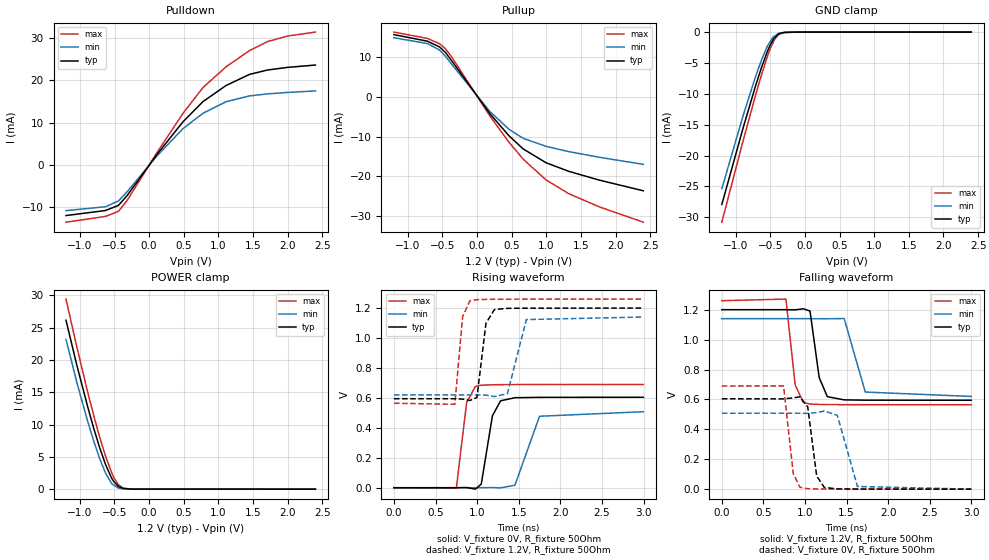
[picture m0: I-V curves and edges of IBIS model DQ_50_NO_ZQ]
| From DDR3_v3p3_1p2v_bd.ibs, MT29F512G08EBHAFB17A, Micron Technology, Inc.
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| MODEL DQ_50_NO_ZQ (50 Ohm Data I/O with no ODT, With No Cal)
[Model]   DQ_50_NO_ZQ
Model_type   I/O
Vinl = 450.000mV
Vinh = 750.000mV
Vmeas = 600.000mV
Vref = 600.000mV
Cref = 0.0pF
Rref = 50.000Ohm
|   typ   min   max
|C_comp   1.240pF   1.143pF   1.340pF
C_comp_pullup   0.6200pF   0.5715pF   0.6700pF
C_comp_pulldown   0.6200pF   0.5715pF   0.6700pF
[Model Spec]
| Input threshold voltage corners
Vinl   0.4500V   0.4200V   0.4800V
Vinh   0.7500V   0.7200V   0.7800V
| Measurement voltage corners
Vmeas   0.6000V   0.5700V   0.6300V
| Timing spec test load voltage corners
Vref   0.6000V   0.5700V   0.6300V
| Dynamic Overshoot Parameters from ONFI4 Specification
D_overshoot_ampl_h   0.80   NA   NA
D_overshoot_ampl_l   0.80   NA   NA
D_overshoot_area_h   0.38n   NA   NA
D_overshoot_area_l   0.38n   NA   NA
[Receiver Thresholds]
Vth   =  0.600V
Vth_min  =  0.5880V
Vth_max  =  0.6120V
Vinh_ac  =  0.150V
Vinh_dc  =  0.100V
Vinl_ac  = -0.150V
Vinl_dc  = -0.100V
Tslew_ac =  5.000ns |Not specified, so set to high value
Threshold_sensitivity = 0.50
Reference_supply Pullup_ref
[Voltage Range]   1.2000V   1.1400V   1.2600V
[Pullup Reference]   1.2000V   1.1400V   1.2600V
| Junction Temperature (Ambient temp is 35C typ, 70C min, 0C max)
[Temperature Range]   50.0   85.0   0.0
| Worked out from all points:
|   slope of the pulldown table from 0 to 0.18 V, typ, clamps not added: 45.8 ohm
|   slope of the pullup table from 0 to 0.18 V, typ, clamps not added: 43.5 ohm
|   GND clamp passes 1 mA (typ) near -0.44 V on its own axis
|   POWER clamp passes 1 mA (typ) near -0.50 V on its own axis
|   falling waveform, V_fixture 1.2V, R_fixture 50Ohm: 20-80 % time 86.1ps typ, 112ps min, 67.3ps max; typ from 1.2 V to 0.594 V
|   rising waveform, V_fixture 0V, R_fixture 50Ohm: 20-80 % time 104ps typ, 150ps min, 72.6ps max; typ from 0 V to 0.604 V
|   rising waveform, V_fixture 1.2V, R_fixture 50Ohm: 20-80 % time 67.9ps typ, 93.3ps min, 50.9ps max; typ from 0.594 V to 1.2 V
|   falling waveform, V_fixture 0V, R_fixture 50Ohm: 20-80 % time 74.8ps typ, 100ps min, 58.5ps max; typ from 0.604 V to 0 V
[Pulldown]
|   Voltage   I(typ)   I(min)   I(max)
-1.2V     -11.9mA    -10.74mA   -13.46mA
-630mV    -10.71mA   -9.821mA   -12.1mA
-442.7mV  -9.496mA   -8.468mA   -10.91mA
-316.7mV  -7.168mA   -6.268mA   -8.307mA
114.4mV   2.519mA    2.175mA    2.96mA
488.3mV   10.18mA    8.565mA    12.17mA
777.9mV   14.95mA    12.2mA     18.26mA
1.11V     18.72mA    14.91mA    23.12mA
1.447V    21.33mA    16.27mA    26.93mA
1.711V    22.38mA    16.75mA    29.08mA
1.997V    22.99mA    17.09mA    30.37mA
2.4V      23.54mA    17.45mA    31.3mA
[GND Clamp]
|   Voltage   I(typ)   I(min)   I(max)
-1.2V     -27.93mA   -25.37mA   -30.8mA
-889.9mV  -15.42mA   -13.44mA   -17.47mA
-716.6mV  -8.847mA   -7.332mA   -10.36mA
-630mV    -5.822mA   -4.6mA     -7.024mA
-542.2mV  -3.131mA   -2.274mA   -3.968mA
-509.5mV  -2.31mA    -1.674mA   -2.913mA
-464.7mV  -1.308mA   -850.6uA   -1.787mA
-442.7mV  -972.8uA   -663uA     -1.241mA
-376mV    -282.1uA   -172.7uA   -322.1uA
-298.8mV  -41.79uA   -56.73uA   -89.82uA
-118.9mV  -137.7nA   -4.668uA   -5.382nA
2.402V    0A         0A         0A
[Pullup]
|   Voltage   I(typ)   I(min)   I(max)
-1.2V     15.67mA    14.89mA    16.31mA
-716.6mV  14.02mA    13.42mA    14.71mA
-542.2mV  12.57mA    11.8mA     13.39mA
-460.4mV  11.25mA    10.3mA     12.17mA
-377.2mV  9.358mA    8.439mA    10.34mA
185.1mV   -4.251mA   -3.681mA   -4.834mA
456.9mV   -9.743mA   -8.135mA   -11.35mA
666.1mV   -13.13mA   -10.46mA   -15.71mA
996.2mV   -16.61mA   -12.48mA   -20.95mA
1.321V    -18.75mA   -13.79mA   -24.37mA
1.759V    -20.96mA   -15.21mA   -27.69mA
2.4V      -23.67mA   -17.01mA   -31.58mA
[POWER Clamp]
|   Voltage   I(typ)   I(min)   I(max)
-1.2V     26.15mA    23.18mA    29.43mA
-1.043V   19.17mA    16.5mA     21.98mA
-889.9mV  12.88mA    10.62mA    15.16mA
-803.3mV  9.553mA    7.573mA    11.54mA
-716.6mV  6.51mA     4.82mA     8.158mA
-628.9mV  3.814mA    2.487mA    5.103mA
-542.2mV  1.733mA    889.2uA    2.608mA
-509.5mV  1.179mA    605.7uA    1.789mA
-442.7mV  400.4uA    165.9uA    681.8uA
-376mV    116.7uA    36.78uA    181.2uA
-257.5mV  4.462uA    7.551uA    6.726uA
2.402V    0A         0A         0A
[Ramp]
R_load = 50
|   typ   min   max
dV/dt_r 3.6255E-01/1.0412E-10   3.0452E-01/1.4883E-10   4.1380E-01/7.2387E-11
dV/dt_f 3.6334E-01/8.5651E-11   3.1198E-01/1.1196E-10   4.1739E-01/6.7087E-11
[Falling Waveform]
V_fixture = 1.2V
V_fixture_min = 1.14V
V_fixture_max = 1.26V
R_fixture = 50Ohm
C_fixture = 0F
|   Time   V(typ)   V(min)   V(max)
0s        1.2V       1.14V      1.26V
770ps     1.2V       1.14V      1.271V
882ps     1.199V     1.14V      696.3mV
980ps     1.206V     1.14V      579.4mV
1.06ns    1.191V     1.14V      569.4mV
1.17ns    746.2mV    1.139V     566.6mV
1.268ns   618.5mV    1.139V     565.6mV
1.47ns    597mV      1.141V     564.9mV
1.724ns   595mV      649.3mV    564.6mV
2.998ns   594.4mV    619.9mV    564.4mV
[Rising Waveform]
V_fixture = 0V
V_fixture_min = 0V
V_fixture_max = 0V
R_fixture = 50Ohm
C_fixture = 0F
|   Time   V(typ)   V(min)   V(max)
0s        102.4uV    210.4uV    27.51uV
750ps     242.3uV    94.29uV    -3.664mV
874ps     1.331mV    57.87uV    569.4mV
980ps     -9.511mV   39.28uV    677mV
1.05ns    24.86mV    332.1uV    684.8mV
1.184ns   480.6mV    1.148mV    687.6mV
1.282ns   580.5mV    -761uV     688.4mV
1.454ns   601.2mV    16.45mV    689mV
1.75ns    603.6mV    477.4mV    689.4mV
2.998ns   604.4mV    507.7mV    689.7mV
[Rising Waveform]
V_fixture = 1.2V
V_fixture_min = 1.14V
V_fixture_max = 1.26V
R_fixture = 50Ohm
C_fixture = 0F
|   Time   V(typ)   V(min)   V(max)
0s        594.4mV    620mV      564.4mV
732ps     594.5mV    619.8mV    557.4mV
826ps     591.9mV    619.7mV    1.143V
914ps     582.7mV    619.7mV    1.249V
998ps     603mV      620mV      1.256V
1.106ns   1.098V     618.2mV    1.258V
1.208ns   1.19V      608.9mV    1.259V
1.364ns   1.198V     628.1mV    1.259V
1.592ns   1.199V     1.123V     1.26V
2.998ns   1.2V       1.14V      1.26V
[Falling Waveform]
|Gnd
V_fixture = 0V
V_fixture_min = 0V
V_fixture_max = 0V
R_fixture = 50Ohm
C_fixture = 0F
|   Time   V(typ)   V(min)   V(max)
0s        604.3mV    507.7mV    689.7mV
742ps     603.8mV    507.9mV    690.2mV
858ps     610.4mV    508mV      105.6mV
938ps     617.4mV    507.6mV    12.87mV
1.032ns   550.4mV    507mV      3.344mV
1.14ns    88.04mV    511.8mV    1.701mV
1.232ns   11.33mV    522.8mV    1.159mV
1.388ns   1.824mV    493.8mV    694.5uV
1.63ns    742.9uV    17.86mV    385uV
2.998ns   86.27uV    166.3uV    20.42uV
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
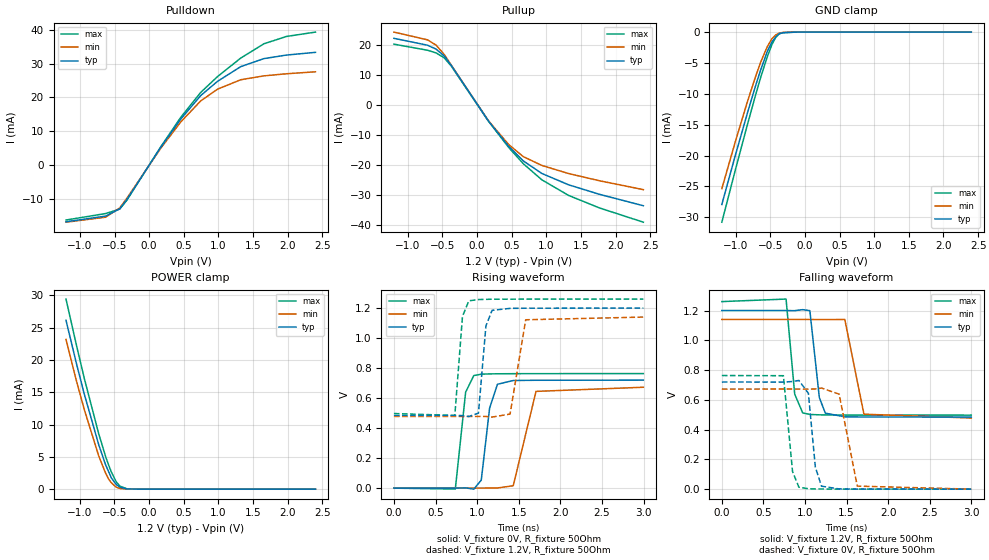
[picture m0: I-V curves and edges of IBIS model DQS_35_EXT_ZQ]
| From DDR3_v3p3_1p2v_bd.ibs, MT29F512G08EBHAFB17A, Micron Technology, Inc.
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| MODEL DQS_35_EXT_ZQ (35 Ohm Data Strobe I/O with no ODT, With ZQ Cal)
[Model]   DQS_35_EXT_ZQ
Model_type   I/O
Vinl = 450.000mV
Vinh = 750.000mV
Vmeas = 600.000mV
Vref = 600.000mV
Cref = 0.0pF
Rref = 50.000Ohm
|   typ   min   max
|C_comp   1.240pF   1.143pF   1.340pF
C_comp_pullup   0.6200pF   0.5715pF   0.6700pF
C_comp_pulldown   0.6200pF   0.5715pF   0.6700pF
[Model Spec]
| Input threshold voltage corners
Vinl   0.4500V   0.4200V   0.4800V
Vinh   0.7500V   0.7200V   0.7800V
| Measurement voltage corners
Vmeas   0.6000V   0.5700V   0.6300V
| Timing spec test load voltage corners
Vref   0.6000V   0.5700V   0.6300V
| Dynamic Overshoot Parameters from ONFI4 Specification
D_overshoot_ampl_h   0.80   NA   NA
D_overshoot_ampl_l   0.80   NA   NA
D_overshoot_area_h   0.38n   NA   NA
D_overshoot_area_l   0.38n   NA   NA
[Receiver Thresholds]
|Vth   =  0.600V
|Vth_min  =  0.5880V
|Vth_max  =  0.6120V
|Vinh_ac  =  0.150V
|Vinh_dc  =  0.100V
|Vinl_ac  = -0.150V
|Vinl_dc  = -0.100V
|Tslew_ac =  5.000ns |Not specified, so set to high value
|Threshold_sensitivity = 0.50
|Reference_supply Pullup_ref
Vcross_low   = 0.480V
Vcross_high  = 0.720V
Vdiff_ac   = 300mV
Vdiff_dc   = 200mV
Tdiffslew_ac = 10.000ns |Not specified, so set to high value
[Voltage Range]   1.2000V   1.1400V   1.2600V
[Pullup Reference]   1.2000V   1.1400V   1.2600V
| Junction Temperature (Ambient temp is 35C typ, 70C min, 0C max)
[Temperature Range]   50.0   85.0   0.0
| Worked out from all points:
|   slope of the pulldown table from 0 to 0.18 V, typ, clamps not added: 32.3 ohm
|   slope of the pullup table from 0 to 0.18 V, typ, clamps not added: 30.7 ohm
|   GND clamp passes 1 mA (typ) near -0.44 V on its own axis
|   POWER clamp passes 1 mA (typ) near -0.49 V on its own axis
|   falling waveform, V_fixture 1.2V, R_fixture 50Ohm: 20-80 % time 73.8ps typ, 92ps min, 62.6ps max; typ from 1.2 V to 0.484 V
|   rising waveform, V_fixture 0V, R_fixture 50Ohm: 20-80 % time 90.4ps typ, 122ps min, 66.9ps max; typ from 0 V to 0.72 V
|   rising waveform, V_fixture 1.2V, R_fixture 50Ohm: 20-80 % time 56.5ps typ, 73.7ps min, 44.8ps max; typ from 0.484 V to 1.2 V
|   falling waveform, V_fixture 0V, R_fixture 50Ohm: 20-80 % time 68.4ps typ, 92.3ps min, 56ps max; typ from 0.72 V to 0 V
[Pulldown]
|   Voltage   I(typ)   I(min)   I(max)
-1.2V     -16.86mA   -16.98mA   -16.34mA
-629.2mV  -15.18mA   -15.51mA   -14.42mA
-423.8mV  -12.99mA   -12.74mA   -13.09mA
-320.5mV  -10.25mA   -9.863mA   -10.44mA
163.4mV   5.072mA    4.806mA    5.216mA
456.9mV   13.59mA    12.73mA    14.1mA
744.8mV   20.54mA    18.95mA    21.47mA
986.5mV   24.74mA    22.42mA    26.14mA
1.322V    29.1mA     25.21mA    31.63mA
1.656V    31.47mA    26.36mA    35.86mA
1.98V     32.52mA    26.98mA    38.03mA
2.4V      33.33mA    27.57mA    39.33mA
[GND Clamp]
|   Voltage   I(typ)   I(min)   I(max)
-1.2V     -27.93mA   -25.37mA   -30.8mA
-1.001V   -19.8mA    -17.6mA    -22.17mA
-831.8mV  -13.17mA   -11.32mA   -15.04mA
-715.2mV  -8.785mA   -7.288mA   -10.3mA
-639.3mV  -6.135mA   -4.883mA   -7.353mA
-544.8mV  -3.169mA   -2.381mA   -4.033mA
-475.5mV  -1.572mA   -1.055mA   -1.987mA
-423.8mV  -806.4uA   -480uA     -904.5uA
-372.2mV  -243.3uA   -177uA     -295.9uA
-320.5mV  -109.7uA   -55.24uA   -92.33uA
-118.9mV  0A         0A         -721.1nA
2.402V    0A         0A         0A
[Pullup]
|   Voltage   I(typ)   I(min)   I(max)
-1.2V     22.12mA    24.19mA    20.18mA
-715.2mV  19.83mA    21.61mA    18.16mA
-591.2mV  18.53mA    19.86mA    17.27mA
-474.2mV  16.25mA    16.76mA    15.63mA
-372.2mV  13.1mA     13.2mA     12.89mA
163.4mV   -5.339mA   -5.249mA   -5.385mA
456.9mV   -13.8mA    -13.21mA   -14.18mA
669.6mV   -18.66mA   -17.24mA   -19.61mA
936mV     -22.81mA   -20.14mA   -24.92mA
1.321V    -26.56mA   -22.82mA   -30.09mA
1.765V    -29.72mA   -25.21mA   -34.24mA
2.4V      -33.52mA   -28.17mA   -38.99mA
[POWER Clamp]
|   Voltage   I(typ)   I(min)   I(max)
-1.2V     26.15mA    23.18mA    29.43mA
-1.045V   19.27mA    16.59mA    22.09mA
-934.4mV  14.65mA    12.27mA    17.09mA
-728mV    6.895mA    5.162mA    8.593mA
-631.2mV  3.86mA     2.547mA    5.163mA
-590.1mV  2.845mA    1.66mA     3.888mA
-544.8mV  1.74mA     985.1uA    2.649mA
-475.5mV  736.6uA    310.2uA    1.155mA
-422.6mV  325.1uA    108.6uA    475.8uA
-320.5mV  34.77uA    7.16uA     55.39uA
-118.9mV  345.5nA    0A         220.3nA
2.402V    0A         0A         0A
[Ramp]
R_load = 50
|   typ   min   max
dV/dt_r 4.3179E-01/8.9457E-11   4.0333E-01/1.2160E-10   4.5802E-01/6.6614E-11
dV/dt_f 4.2953E-01/7.3359E-11   3.9722E-01/9.1640E-11   4.5760E-01/6.2165E-11
[Falling Waveform]
V_fixture = 1.2V
V_fixture_min = 1.14V
V_fixture_max = 1.26V
R_fixture = 50Ohm
C_fixture = 0F
|   Time   V(typ)   V(min)   V(max)
0s        1.2V       1.14V      1.26V
772ps     1.2V       1.14V      1.277V
876ps     1.199V     1.14V      638.1mV
972ps     1.206V     1.14V      512.2mV
1.058ns   1.199V     1.14V      502mV
1.172ns   615mV      1.139V     499.3mV
1.244ns   510.5mV    1.139V     498.6mV
1.478ns   485.9mV    1.14V      497.8mV
1.708ns   484.8mV    503.6mV    497.6mV
2.998ns   484.1mV    477.9mV    497.3mV
[Rising Waveform]
V_fixture = 0V
V_fixture_min = 0V
V_fixture_max = 0V
R_fixture = 50Ohm
C_fixture = 0F
|   Time   V(typ)   V(min)   V(max)
0s        95.85uV    205.5uV    27.18uV
738ps     103.3uV    97.07uV    -5.894mV
862ps     1.65mV     58.53uV    639.6mV
960ps     -6.741mV   37.64uV    750.4mV
1.05ns    53.79mV    271.6uV    759.5mV
1.15ns    533.3mV    1.274mV    761.3mV
1.244ns   692.2mV    1.268mV    762.1mV
1.434ns   717.3mV    15.89mV    762.7mV
1.708ns   718.9mV    644.8mV    763.1mV
2.998ns   719.7mV    672.4mV    763.4mV
[Rising Waveform]
V_fixture = 1.2V
V_fixture_min = 1.14V
V_fixture_max = 1.26V
R_fixture = 50Ohm
C_fixture = 0F
|   Time   V(typ)   V(min)   V(max)
0s        484.1mV    477.9mV    497.3mV
732ps     484.2mV    477.7mV    484.4mV
824ps     483.5mV    477.7mV    1.144V
900ps     477.3mV    477.7mV    1.248V
1.016ns   499.9mV    477.9mV    1.257V
1.106ns   1.082V     477.7mV    1.258V
1.18ns    1.185V     473.7mV    1.259V
1.396ns   1.198V     493.5mV    1.259V
1.584ns   1.199V     1.122V     1.26V
2.998ns   1.2V       1.14V      1.26V
[Falling Waveform]
|Gnd
V_fixture = 0V
V_fixture_min = 0V
V_fixture_max = 0V
R_fixture = 50Ohm
C_fixture = 0F
|   Time   V(typ)   V(min)   V(max)
0s        719.7mV    672.4mV    763.4mV
740ps     719.3mV    672.6mV    762.1mV
850ps     723.2mV    672.6mV    118.6mV
926ps     730.2mV    672.4mV    13.34mV
1.04ns    644.6mV    671.9mV    2.74mV
1.124ns   147.5mV    673.3mV    1.709mV
1.198ns   20.13mV    679.2mV    1.197mV
1.41ns    1.478mV    638.3mV    612.1uV
1.628ns   722.1uV    20.47mV    366.7uV
2.998ns   81.7uV     169.4uV    16.57uV
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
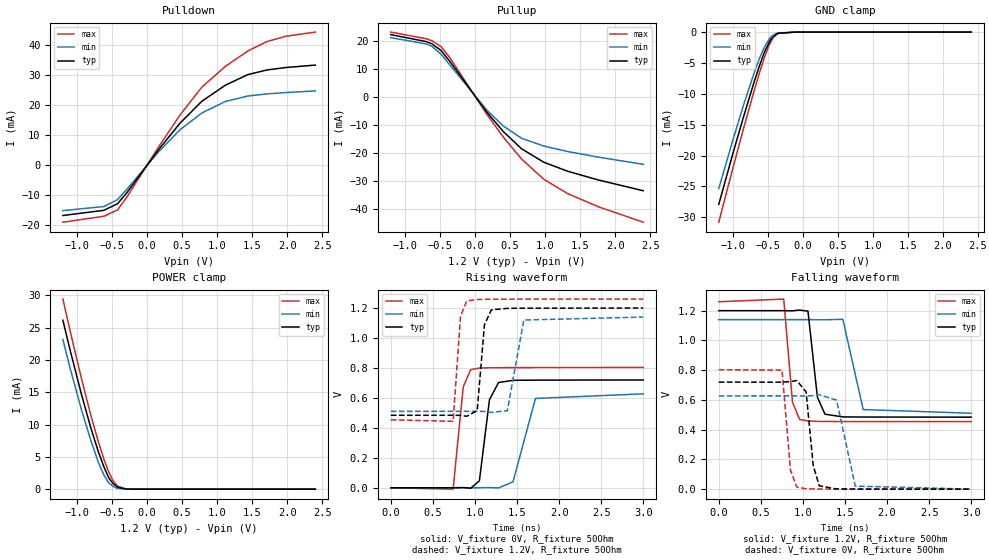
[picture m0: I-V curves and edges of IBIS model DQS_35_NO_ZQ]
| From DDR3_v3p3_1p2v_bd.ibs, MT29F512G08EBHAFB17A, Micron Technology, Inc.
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| MODEL DQS_35_NO_ZQ (35 Ohm Data Strobe I/O with no ODT, With No Cal)
[Model]   DQS_35_NO_ZQ
Model_type   I/O
Vinl = 450.000mV
Vinh = 750.000mV
Vmeas = 600.000mV
Vref = 600.000mV
Cref = 0.0pF
Rref = 50.000Ohm
|   typ   min   max
|C_comp   1.240pF   1.143pF   1.340pF
C_comp_pullup   0.6200pF   0.5715pF   0.6700pF
C_comp_pulldown   0.6200pF   0.5715pF   0.6700pF
[Model Spec]
| Input threshold voltage corners
Vinl   0.4500V   0.4200V   0.4800V
Vinh   0.7500V   0.7200V   0.7800V
| Measurement voltage corners
Vmeas   0.6000V   0.5700V   0.6300V
| Timing spec test load voltage corners
Vref   0.6000V   0.5700V   0.6300V
| Dynamic Overshoot Parameters from ONFI4 Specification
D_overshoot_ampl_h   0.80   NA   NA
D_overshoot_ampl_l   0.80   NA   NA
D_overshoot_area_h   0.38n   NA   NA
D_overshoot_area_l   0.38n   NA   NA
[Receiver Thresholds]
|Vth   =  0.600V
|Vth_min  =  0.5880V
|Vth_max  =  0.6120V
|Vinh_ac  =  0.150V
|Vinh_dc  =  0.100V
|Vinl_ac  = -0.150V
|Vinl_dc  = -0.100V
|Tslew_ac =  5.000ns |Not specified, so set to high value
|Threshold_sensitivity = 0.50
|Reference_supply Pullup_ref
Vcross_low   = 0.480V
Vcross_high  = 0.720V
Vdiff_ac   = 300mV
Vdiff_dc   = 200mV
Tdiffslew_ac = 10.000ns |Not specified, so set to high value
[Voltage Range]   1.2000V   1.1400V   1.2600V
[Pullup Reference]   1.2000V   1.1400V   1.2600V
| Junction Temperature (Ambient temp is 35C typ, 70C min, 0C max)
[Temperature Range]   50.0   85.0   0.0
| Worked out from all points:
|   slope of the pulldown table from 0 to 0.18 V, typ, clamps not added: 32.3 ohm
|   slope of the pullup table from 0 to 0.18 V, typ, clamps not added: 30.7 ohm
|   GND clamp passes 1 mA (typ) near -0.44 V on its own axis
|   POWER clamp passes 1 mA (typ) near -0.49 V on its own axis
|   falling waveform, V_fixture 1.2V, R_fixture 50Ohm: 20-80 % time 73.9ps typ, 97.1ps min, 57.8ps max; typ from 1.2 V to 0.484 V
|   rising waveform, V_fixture 0V, R_fixture 50Ohm: 20-80 % time 90.1ps typ, 133ps min, 62.2ps max; typ from 0 V to 0.72 V
|   rising waveform, V_fixture 1.2V, R_fixture 50Ohm: 20-80 % time 56.3ps typ, 76ps min, 42.8ps max; typ from 0.484 V to 1.2 V
|   falling waveform, V_fixture 0V, R_fixture 50Ohm: 20-80 % time 68.9ps typ, 96.1ps min, 53.2ps max; typ from 0.72 V to 0 V
[Pulldown]
|   Voltage   I(typ)   I(min)   I(max)
-1.2V     -16.86mA   -15.23mA   -19.09mA
-615.2mV  -15.12mA   -13.87mA   -17.11mA
-421.3mV  -12.94mA   -11.55mA   -15.02mA
-290.4mV  -9.333mA   -8.176mA   -10.81mA
161.2mV   5.001mA    4.302mA    5.889mA
470.4mV   13.95mA    11.75mA    16.66mA
782mV     21.27mA    17.35mA    25.98mA
1.12V     26.66mA    21.21mA    32.95mA
1.438V    30.15mA    23.01mA    38.04mA
1.708V    31.69mA    23.71mA    41.17mA
1.98V     32.52mA    24.17mA    42.95mA
2.4V      33.33mA    24.71mA    44.34mA
[GND Clamp]
|   Voltage   I(typ)   I(min)   I(max)
-1.2V     -27.93mA   -25.37mA   -30.8mA
-1.001V   -19.8mA    -17.6mA    -22.17mA
-852.3mV  -13.96mA   -12.06mA   -15.89mA
-693.8mV  -8.039mA   -6.581mA   -9.464mA
-614mV    -5.316mA   -4.134mA   -6.424mA
-544.8mV  -3.169mA   -2.365mA   -4.015mA
-483.6mV  -1.759mA   -1.213mA   -2.185mA
-460.8mV  -1.234mA   -813.7uA   -1.698mA
-421.3mV  -777.3uA   -482.6uA   -857uA
-358.3mV  -207.5uA   -134.2uA   -221.1uA
-107.6mV  0A         0A         -190.2nA
2.402V    0A         0A         0A
[Pullup]
|   Voltage   I(typ)   I(min)   I(max)
-1.2V     22.12mA    21.04mA    23.03mA
-693.8mV  19.64mA    18.82mA    20.65mA
-614mV    18.85mA    17.96mA    19.95mA
-484.3mV  16.48mA    15.19mA    17.87mA
-357.1mV  12.56mA    11.3mA     13.89mA
169.6mV   -5.536mA   -4.8mA     -6.293mA
405.2mV   -12.44mA   -10.47mA   -14.41mA
664.8mV   -18.56mA   -14.81mA   -22.21mA
982.3mV   -23.36mA   -17.59mA   -29.43mA
1.321V    -26.56mA   -19.53mA   -34.52mA
1.761V    -29.69mA   -21.55mA   -39.24mA
2.4V      -33.52mA   -24.09mA   -44.73mA
[POWER Clamp]
|   Voltage   I(typ)   I(min)   I(max)
-1.2V     26.15mA    23.18mA    29.43mA
-1.097V   21.52mA    18.73mA    24.5mA
-931mV    14.51mA    12.14mA    16.94mA
-800.4mV  9.443mA    7.504mA    11.41mA
-693.8mV  5.787mA    4.158mA    7.333mA
-614mV    3.434mA    2.151mA    4.606mA
-546mV    1.761mA    987.4uA    2.65mA
-484.3mV  864.2uA    416.9uA    1.298mA
-420.1mV  312uA      120.1uA    451.4uA
-295.3mV  12.82uA    8.023uA    30.55uA
-118.9mV  345.5nA    0A         0A
2.402V    0A         0A         0A
[Ramp]
R_load = 50
|   typ   min   max
dV/dt_r 4.3179E-01/8.9376E-11   3.7625E-01/1.3207E-10   4.8191E-01/6.1711E-11
dV/dt_f 4.2953E-01/7.3479E-11   3.7776E-01/9.6593E-11   4.8349E-01/5.7519E-11
[Falling Waveform]
V_fixture = 1.2V
V_fixture_min = 1.14V
V_fixture_max = 1.26V
R_fixture = 50Ohm
C_fixture = 0F
|   Time   V(typ)   V(min)   V(max)
0s        1.2V       1.14V      1.26V
772ps     1.2V       1.14V      1.278V
876ps     1.199V     1.14V      584.5mV
960ps     1.204V     1.14V      469.5mV
1.06ns    1.197V     1.14V      458.2mV
1.172ns   618mV      1.139V     455.9mV
1.262ns   503.9mV    1.139V     455.2mV
1.474ns   485.9mV    1.142V     454.7mV
1.716ns   484.8mV    535.2mV    454.4mV
2.998ns   484.1mV    510.3mV    454.2mV
[Rising Waveform]
V_fixture = 0V
V_fixture_min = 0V
V_fixture_max = 0V
R_fixture = 50Ohm
C_fixture = 0F
|   Time   V(typ)   V(min)   V(max)
0s        96.6uV     205.2uV    25.34uV
740ps     81.11uV    95.8uV     -9.124mV
860ps     1.619mV    58.54uV    673.2mV
948ps     -3.318mV   39.55uV    788.7mV
1.052ns   46.42mV    318.3uV    799.6mV
1.172ns   588.5mV    1.345mV    801.5mV
1.28ns    703mV      -577.8uV   802.1mV
1.452ns   717.6mV    40.3mV     802.6mV
1.718ns   718.9mV    596.6mV    802.9mV
2.998ns   719.7mV    627.3mV    803.2mV
[Rising Waveform]
V_fixture = 1.2V
V_fixture_min = 1.14V
V_fixture_max = 1.26V
R_fixture = 50Ohm
C_fixture = 0F
|   Time   V(typ)   V(min)   V(max)
0s        484.1mV    510.3mV    454.2mV
740ps     484.2mV    510.1mV    443.6mV
828ps     483.5mV    510.1mV    1.144V
902ps     477.6mV    510.1mV    1.248V
1.026ns   514.9mV    510.4mV    1.257V
1.112ns   1.088V     509.7mV    1.258V
1.194ns   1.188V     503.9mV    1.259V
1.384ns   1.198V     514.5mV    1.259V
1.58ns    1.199V     1.12V      1.26V
2.998ns   1.2V       1.14V      1.26V
[Falling Waveform]
|Gnd
V_fixture = 0V
V_fixture_min = 0V
V_fixture_max = 0V
R_fixture = 50Ohm
C_fixture = 0F
|   Time   V(typ)   V(min)   V(max)
0s        719.7mV    627.2mV    803.2mV
752ps     719.2mV    627.5mV    800.2mV
852ps     723.3mV    627.5mV    128.7mV
928ps     730.2mV    627.2mV    13.09mV
1.038ns   653.2mV    626.7mV    2.731mV
1.122ns   160.4mV    628.4mV    1.663mV
1.194ns   22.53mV    635.2mV    1.172mV
1.4ns     1.564mV    598.2mV    607.2uV
1.622ns   727.4uV    20.51mV    357.3uV
2.998ns   77.61uV    167.7uV    15.93uV
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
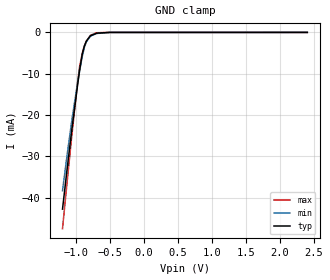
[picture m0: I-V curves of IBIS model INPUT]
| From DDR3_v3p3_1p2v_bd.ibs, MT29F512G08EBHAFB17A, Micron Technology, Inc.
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| MODEL INPUT (Input Input Model)
[Model]   INPUT
Model_type   Input
Vinl = 450.000mV
Vinh = 750.000mV
|   typ   min   max
|C_comp   1.984pF   1.826pF   2.126pF
C_comp_power_clamp   0.9920pF   0.9130pF   1.0630pF
C_comp_gnd_clamp   0.9920pF   0.9130pF   1.0630pF
[Model Spec]
| Input threshold voltage corners
Vinl   0.4500V   0.4200V   0.4800V
Vinh   0.7500V   0.7200V   0.7800V
| Dynamic Overshoot Parameters from ONFI4 Specification
D_overshoot_ampl_h   0.80   NA   NA
D_overshoot_ampl_l   0.80   NA   NA
D_overshoot_area_h   0.38n   NA   NA
D_overshoot_area_l   0.38n   NA   NA
[Receiver Thresholds]
Vth   =  0.600V
Vth_min  =  0.5880V
Vth_max  =  0.6120V
Vinh_ac  =  0.150V
Vinh_dc  =  0.100V
Vinl_ac  = -0.150V
Vinl_dc  = -0.100V
Tslew_ac =  5.000ns |Not specified, so set to high value
Threshold_sensitivity = 0.50
Reference_supply Power_clamp_ref
[Voltage Range]   1.2000V   1.1400V   1.2600V
[POWER Clamp Reference]   1.2000V   1.1400V   1.2600V
| Junction Temperature (Ambient temp is 35C typ, 70C min, 0C max)
[Temperature Range]   50.0   85.0   0.0
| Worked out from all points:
|   GND clamp passes 1 mA (typ) near -0.80 V on its own axis
[GND Clamp]
|   Voltage   I(typ)   I(min)   I(max)
-1.2V     -42.73mA   -38.29mA   -47.46mA
-1.13V    -32.69mA   -29.34mA   -35.77mA
-1.06V    -23.12mA   -20.92mA   -24.48mA
-980mV    -12.91mA   -12.36mA   -12.23mA
-950mV    -9.296mA   -9.444mA   -8.433mA
-910mV    -5.286mA   -5.843mA   -5.055mA
-880mV    -3.352mA   -3.711mA   -3.357mA
-850mV    -2.123mA   -2.283mA   -2.152mA
-790mV    -839.4uA   -917.2uA   -718.8uA
-700mV    -194.7uA   -270.1uA   -91.56uA
-510mV    -4.206uA   -9.012uA   -706.7nA
2.4V      0A         0A         0A
[POWER Clamp]
|   Voltage   I(typ)   I(min)   I(max)
-1.2V     0A         0A         0A
0V        0A         0A         0A
2.4V      0A         0A         0A
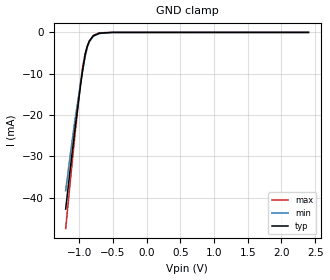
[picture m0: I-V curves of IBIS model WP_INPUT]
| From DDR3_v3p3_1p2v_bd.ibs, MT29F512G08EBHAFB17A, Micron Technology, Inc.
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| MODEL WP_INPUT (WP Input Model)
[Model]   WP_INPUT
Model_type   Input
Vinl = 240.000mV
Vinh = 960.000mV
|   typ   min   max
|C_comp   2.193pF   2.000pF   2.296pF
C_comp_power_clamp   1.0965pF   1.0000pF   1.1480pF
C_comp_gnd_clamp   1.0965pF   1.0000pF   1.1480pF
[Model Spec]
| Input threshold voltage corners
Vinl   0.2400V   0.2280V   0.2520V
Vinh   0.9600V   0.9120V   1.0080V
| Dynamic Overshoot Parameters from ONFI4 Specification
D_overshoot_ampl_h   0.80   NA   NA
D_overshoot_ampl_l   0.80   NA   NA
D_overshoot_area_h   0.38n   NA   NA
D_overshoot_area_l   0.38n   NA   NA
[Voltage Range]   1.2000V   1.1400V   1.2600V
| Junction Temperature (Ambient temp is 35C typ, 70C min, 0C max)
[Temperature Range]   50.0   85.0   0.0
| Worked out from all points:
|   GND clamp passes 1 mA (typ) near -0.80 V on its own axis
[GND Clamp]
|   Voltage   I(typ)   I(min)   I(max)
-1.2V     -42.73mA   -38.29mA   -47.46mA
-1.13V    -32.69mA   -29.34mA   -35.77mA
-1.06V    -23.12mA   -20.92mA   -24.48mA
-980mV    -12.91mA   -12.36mA   -12.23mA
-950mV    -9.296mA   -9.444mA   -8.433mA
-910mV    -5.286mA   -5.843mA   -5.055mA
-880mV    -3.352mA   -3.711mA   -3.357mA
-850mV    -2.123mA   -2.283mA   -2.152mA
-790mV    -839.4uA   -917.2uA   -718.8uA
-700mV    -194.7uA   -270.1uA   -91.56uA
-510mV    -4.206uA   -9.012uA   -706.7nA
2.4V      0A         0A         0A
[POWER Clamp]
|   Voltage   I(typ)   I(min)   I(max)
-1.2V     0A         0A         0A
0V        0A         0A         0A
2.4V      0A         0A         0A
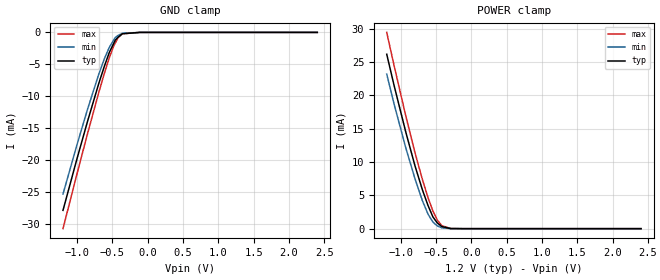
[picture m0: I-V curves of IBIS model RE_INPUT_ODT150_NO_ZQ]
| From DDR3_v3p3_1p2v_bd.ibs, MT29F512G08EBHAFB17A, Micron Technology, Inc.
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| MODEL RE_INPUT_ODT150_NO_ZQ (RE Input Model with 150ohm ODT, With No Cal)
[Model]   RE_INPUT_ODT150_NO_ZQ
Model_type   Input
Vinl = 450.000mV
Vinh = 750.000mV
|   typ   min   max
|C_comp   1.209pF   1.095pF   1.326pF
C_comp_power_clamp   0.6045pF   0.5475pF   0.6630pF
C_comp_gnd_clamp   0.6045pF   0.5475pF   0.6630pF
| Note: C_comp changes when the ODT circuit is enabled.
[Model Spec]
| Input threshold voltage corners
Vinl   0.4500V   0.4200V   0.4800V
Vinh   0.7500V   0.7200V   0.7800V
| Dynamic Overshoot Parameters from ONFI4 Specification
D_overshoot_ampl_h   0.80   NA   NA
D_overshoot_ampl_l   0.80   NA   NA
D_overshoot_area_h   0.38n   NA   NA
D_overshoot_area_l   0.38n   NA   NA
[Receiver Thresholds]
|Vth   =  0.600V
|Vth_min  =  0.5880V
|Vth_max  =  0.6120V
|Vinh_ac  =  0.150V
|Vinh_dc  =  0.100V
|Vinl_ac  = -0.150V
|Vinl_dc  = -0.100V
|Tslew_ac =  5.000ns |Not specified, so set to high value
|Threshold_sensitivity = 0.50
|Reference_supply Power_clamp_ref
Vcross_low   = 0.480V
Vcross_high  = 0.720V
Vdiff_ac   = 300mV
Vdiff_dc   = 200mV
Tdiffslew_ac = 10.000ns |Not specified, so set to high value
[Voltage Range]   1.2000V   1.1400V   1.2600V
[POWER Clamp Reference]   1.2000V   1.1400V   1.2600V
| Junction Temperature (Ambient temp is 35C typ, 70C min, 0C max)
[Temperature Range]   50.0   85.0   0.0
[Add Submodel]
| Submodel Name   Mode
150ohm_ODT_NO_ZQ   Non-Driving
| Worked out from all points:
|   GND clamp passes 1 mA (typ) near -0.44 V on its own axis
|   POWER clamp passes 1 mA (typ) near -0.49 V on its own axis
[GND Clamp]
|   Voltage   I(typ)   I(min)   I(max)
-1.2V     -27.93mA   -25.37mA   -30.8mA
-1.001V   -19.8mA    -17.6mA    -22.17mA
-852.3mV  -13.96mA   -12.06mA   -15.89mA
-693.8mV  -8.039mA   -6.581mA   -9.464mA
-614mV    -5.316mA   -4.134mA   -6.424mA
-544.8mV  -3.169mA   -2.365mA   -4.015mA
-483.6mV  -1.759mA   -1.213mA   -2.185mA
-460.8mV  -1.234mA   -813.7uA   -1.698mA
-421.3mV  -777.3uA   -482.6uA   -857uA
-358.3mV  -207.5uA   -134.2uA   -221.1uA
-107.6mV  0A         0A         -190.2nA
2.402V    0A         0A         0A
[POWER Clamp]
|   Voltage   I(typ)   I(min)   I(max)
-1.2V     26.15mA    23.18mA    29.43mA
-1.097V   21.52mA    18.73mA    24.5mA
-931mV    14.51mA    12.14mA    16.94mA
-800.4mV  9.443mA    7.504mA    11.41mA
-693.8mV  5.787mA    4.158mA    7.333mA
-614mV    3.434mA    2.151mA    4.606mA
-546mV    1.761mA    987.4uA    2.65mA
-484.3mV  864.2uA    416.9uA    1.298mA
-420.1mV  312uA      120.1uA    451.4uA
-295.3mV  12.82uA    8.023uA    30.55uA
-118.9mV  345.5nA    0A         0A
2.402V    0A         0A         0A
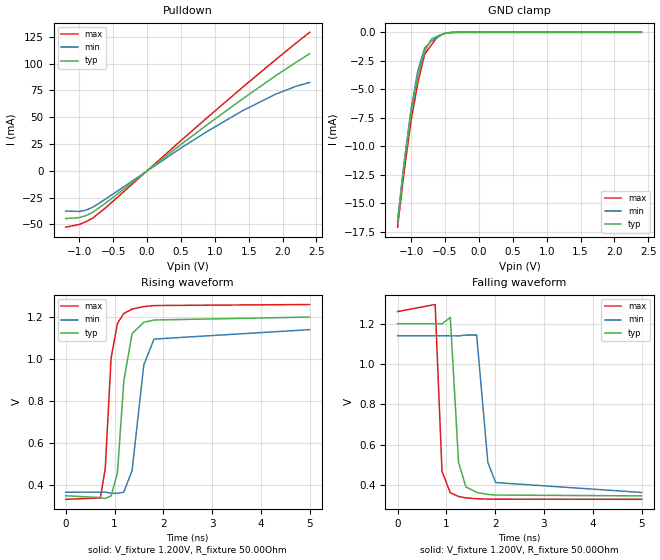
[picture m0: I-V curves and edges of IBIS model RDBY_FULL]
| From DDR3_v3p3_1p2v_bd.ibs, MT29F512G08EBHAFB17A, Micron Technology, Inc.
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| MODEL RDBY_FULL (FULL-Drv RDBY Open-Drain Model)
[Model]   RDBY_FULL
Model_type   Open_drain
Vmeas = 0.600V
Vref = 1.200V
Cref = 50.0pF
Rref = 1000.000Ohm
|   typ   min   max
|C_comp   2.216pF   2.116pF   2.317pF
C_comp_pulldown   2.2160pF   2.1160pF   2.3170pF
[Model Spec]
| Measurement voltage corners
Vmeas   0.600V   0.570V   0.630V
| Timing spec test load voltage corners
Vref   1.200V   1.140V   1.260V
[Voltage Range]   1.2000V   1.1400V   1.2600V
| Junction Temperature (Ambient temp is 35C typ, 70C min, 0C max)
[Temperature Range]   50.0   85.0   0.0
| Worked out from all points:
|   slope of the pulldown table from 0 to 0.18 V, typ, clamps not added: 20.3 ohm
|   GND clamp passes 1 mA (typ) near -0.74 V on its own axis
|   falling waveform, V_fixture 1.200V, R_fixture 50.00Ohm: 20-80 % time 96.5ps typ, 146ps min, 69.8ps max; typ from 1.2 V to 0.347 V
|   rising waveform, V_fixture 1.200V, R_fixture 50.00Ohm: 20-80 % time 164ps typ, 205ps min, 145ps max; typ from 0.347 V to 1.2 V
[Pulldown]
|   Voltage   I(typ)   I(min)   I(max)
-1.2V     -44.58mA   -37.56mA   -52.61mA
-1V       -43.72mA   -38mA      -50.09mA
-900mV    -41.8mA    -36.69mA   -47.49mA
-800mV    -38.68mA   -34.01mA   -44.07mA
-600mV    -29.7mA    -25.91mA   -33.94mA
500mV     24.47mA    21.15mA    28.11mA
900mV     43.52mA    37.16mA    50.18mA
1.4V      66.59mA    55.63mA    77.32mA
1.9V      88.68mA    71.45mA    103.7mA
2.2V      101.2mA    78.79mA    119.1mA
2.4V      109.2mA    82.39mA    129.1mA
[GND Clamp]
|   Voltage   I(typ)   I(min)   I(max)
-1.2V     -16.71mA   -16.48mA   -17.08mA
-1.1V     -11.43mA   -11.23mA   -12.04mA
-1V       -7.033mA   -6.67mA    -7.705mA
-900mV    -3.722mA   -3.328mA   -4.389mA
-800mV    -1.642mA   -1.383mA   -1.908mA
-700mV    -584.7uA   -765.1uA   -1.105mA
-600mV    -307.1uA   -403.2uA   -302.7uA
-500mV    -78.35uA   -59.89uA   -91.74uA
-400mV    -14.27uA   -9.121uA   -8.97uA
-300mV    0A         0A         0A
1.3V      0A         0A         0A
2.4V      0A         0A         0A
[POWER Clamp]
|   Voltage   I(typ)   I(min)   I(max)
-1.2V     0A         0A         0A
0V        0A         0A         0A
2.4V      0A         0A         0A
[Ramp]
R_load = 50.00Ohm
|   typ   min   max
dV/dt_r   511.686mV/164.091ps 465.462mV/204.592ps 557.937mV/144.709ps
dV/dt_f   511.686mV/96.514ps  465.462mV/146.035ps 557.937mV/69.788ps
[Falling Waveform]
V_fixture = 1.200V
V_fixture_min = 1.140V
V_fixture_max = 1.260V
R_fixture = 50.00Ohm
|   Time   V(typ)   V(min)   V(max)
0s        1.2V       1.14V      1.26V
770ps     1.2V       1.14V      1.295V
910ps     1.199V     1.14V      469.1mV
1.08ns    1.231V     1.14V      362.6mV
1.25ns    512.2mV    1.139V     344.4mV
1.4ns     392.1mV    1.144V     337.3mV
1.62ns    364.5mV    1.144V     333.1mV
1.85ns    354.4mV    512.3mV    331.4mV
2.01ns    351.4mV    413.3mV    330.9mV
5ns       347.3mV    364.3mV    330.2mV
[Rising Waveform]
V_fixture = 1.200V
V_fixture_min = 1.140V
V_fixture_max = 1.260V
R_fixture = 50.00Ohm
|   Time   V(typ)   V(min)   V(max)
0s        347.3mV    364.3mV    330.2mV
710ps     338.5mV    364.4mV    337mV
810ps     334.3mV    364.9mV    475.2mV
930ps     346.7mV    359.6mV    1.004V
1.06ns    456.3mV    358.7mV    1.17V
1.19ns    894.1mV    364.4mV    1.217V
1.36ns    1.121V     467.5mV    1.238V
1.6ns     1.175V     971.6mV    1.25V
1.81ns    1.186V     1.095V     1.255V
5ns       1.2V       1.14V      1.26V
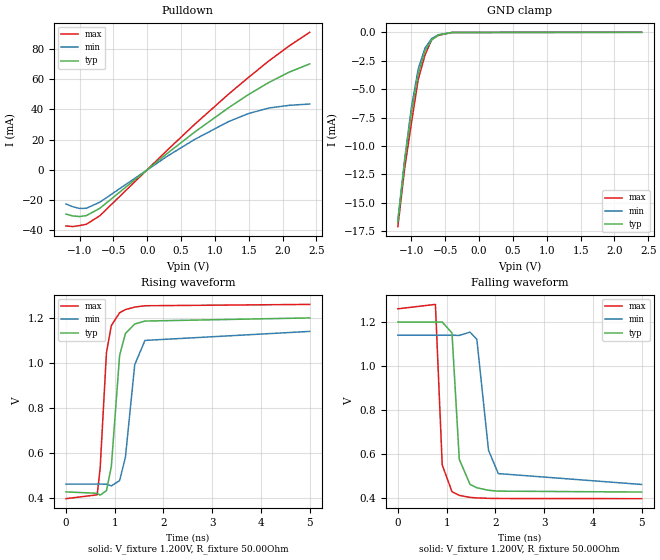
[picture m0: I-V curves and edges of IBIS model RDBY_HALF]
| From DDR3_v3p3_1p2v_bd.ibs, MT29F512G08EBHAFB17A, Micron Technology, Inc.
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| MODEL RDBY_HALF (HALF-Drv RDBY Open-Drain Model)
[Model]   RDBY_HALF
Model_type   Open_drain
Vmeas = 0.600V
Vref = 1.200V
Cref = 50.0pF
Rref = 1000.000Ohm
|   typ   min   max
|C_comp   2.216pF   2.116pF   2.317pF
C_comp_pulldown   2.2160pF   2.1160pF   2.3170pF
[Model Spec]
| Measurement voltage corners
Vmeas   0.600V   0.570V   0.630V
| Timing spec test load voltage corners
Vref   1.200V   1.140V   1.260V
[Voltage Range]   1.2000V   1.1400V   1.2600V
| Junction Temperature (Ambient temp is 35C typ, 70C min, 0C max)
[Temperature Range]   50.0   85.0   0.0
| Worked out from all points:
|   slope of the pulldown table from 0 to 0.18 V, typ, clamps not added: 27.3 ohm
|   GND clamp passes 1 mA (typ) near -0.73 V on its own axis
|   falling waveform, V_fixture 1.200V, R_fixture 50.00Ohm: 20-80 % time 118ps typ, 191ps min, 85.3ps max; typ from 1.2 V to 0.427 V
|   rising waveform, V_fixture 1.200V, R_fixture 50.00Ohm: 20-80 % time 163ps typ, 195ps min, 145ps max; typ from 0.427 V to 1.2 V
[Pulldown]
|   Voltage   I(typ)   I(min)   I(max)
-1.2V     -29.61mA   -22.89mA   -37.49mA
-1.1V     -30.85mA   -24.72mA   -37.91mA
-1V       -31.25mA   -25.84mA   -37.25mA
-900mV    -30.62mA   -25.75mA   -36.4mA
-700mV    -25.75mA   -21.69mA   -30.7mA
300mV     10.93mA    9.013mA    13.08mA
700mV     24.92mA    20.03mA    30.07mA
1.2V      41.1mA     31.91mA    50.13mA
1.5V      50.04mA    37.34mA    61.49mA
1.8V      58.03mA    40.98mA    72.39mA
2.1V      64.89mA    42.76mA    82.35mA
2.4V      70.31mA    43.61mA    91.33mA
[GND Clamp]
|   Voltage   I(typ)   I(min)   I(max)
-1.2V     -16.71mA   -16.48mA   -17.08mA
-1.1V     -11.43mA   -11.15mA   -11.98mA
-1V       -7.034mA   -6.582mA   -7.978mA
-900mV    -3.682mA   -3.233mA   -4.165mA
-800mV    -1.655mA   -1.388mA   -2.01mA
-700mV    -667.9uA   -547.4uA   -629.3uA
-600mV    -241.7uA   -209.4uA   -268.9uA
-400mV    -16.57uA   -14.06uA   -13.26uA
2.4V      0A         0A         0A
[POWER Clamp]
|   Voltage   I(typ)   I(min)   I(max)
-1.2V     0A         0A         0A
0V        0A         0A         0A
2.4V      0A         0A         0A
[Ramp]
R_load = 50.00Ohm
|   typ   min   max
dV/dt_r   463.775mV/162.925ps 407.080mV/194.708ps 517.843mV/145.264ps
dV/dt_f   463.775mV/117.821ps 407.080mV/191.027ps 517.843mV/85.290ps
[Falling Waveform]
V_fixture = 1.200V
V_fixture_min = 1.140V
V_fixture_max = 1.260V
R_fixture = 50.00Ohm
|   Time   V(typ)   V(min)   V(max)
0s        1.2V       1.14V      1.26V
770ps     1.2V       1.14V      1.28V
910ps     1.2V       1.14V      550.4mV
1.11ns    1.15V      1.14V      428.6mV
1.26ns    575.7mV    1.139V     412mV
1.48ns    462.3mV    1.154V     402.8mV
1.62ns    446.7mV    1.121V     400.4mV
1.86ns    435.1mV    616.8mV    398.5mV
2.06ns    431.2mV    511mV      397.8mV
5ns       427.1mV    461.6mV    397mV
[Rising Waveform]
V_fixture = 1.200V
V_fixture_min = 1.140V
V_fixture_max = 1.260V
R_fixture = 50.00Ohm
|   Time   V(typ)   V(min)   V(max)
0s        427.1mV    461.6mV    397mV
640ps     420.9mV    461.7mV    414.2mV
700ps     412.7mV    461.8mV    530mV
830ps     432.6mV    461.2mV    1.046V
930ps     539.4mV    453.7mV    1.166V
1.1ns     1.034V     477.4mV    1.223V
1.22ns    1.131V     582.2mV    1.237V
1.41ns    1.173V     991.9mV    1.248V
1.62ns    1.186V     1.1V       1.254V
5ns       1.2V       1.14V      1.26V
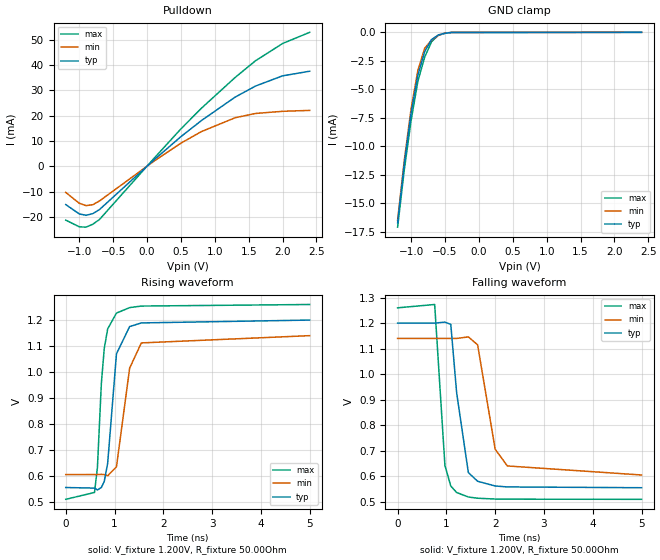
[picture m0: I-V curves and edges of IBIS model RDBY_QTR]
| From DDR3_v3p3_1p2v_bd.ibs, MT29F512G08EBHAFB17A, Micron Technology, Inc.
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| MODEL RDBY_QTR (QTR-Drv RDBY Open-Drain Model)
[Model]   RDBY_QTR
Model_type   Open_drain
Vmeas = 0.600V
Vref = 1.200V
Cref = 50.0pF
Rref = 1000.000Ohm
|   typ   min   max
|C_comp   2.216pF   2.116pF   2.317pF
C_comp_pulldown   2.2160pF   2.1160pF   2.3170pF
[Model Spec]
| Measurement voltage corners
Vmeas   0.600V   0.570V   0.630V
| Timing spec test load voltage corners
Vref   1.200V   1.140V   1.260V
[Voltage Range]   1.2000V   1.1400V   1.2600V
| Junction Temperature (Ambient temp is 35C typ, 70C min, 0C max)
[Temperature Range]   50.0   85.0   0.0
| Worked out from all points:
|   slope of the pulldown table from 0 to 0.18 V, typ, clamps not added: 41.5 ohm
|   GND clamp passes 1 mA (typ) near -0.73 V on its own axis
|   falling waveform, V_fixture 1.200V, R_fixture 50.00Ohm: 20-80 % time 175ps typ, 276ps min, 127ps max; typ from 1.2 V to 0.555 V
|   rising waveform, V_fixture 1.200V, R_fixture 50.00Ohm: 20-80 % time 165ps typ, 203ps min, 145ps max; typ from 0.555 V to 1.2 V
[Pulldown]
|   Voltage   I(typ)   I(min)   I(max)
-1.2V     -15.15mA   -10.34mA   -21.29mA
-1V       -18.84mA   -14.63mA   -23.93mA
-900mV    -19.39mA   -15.57mA   -24.07mA
-800mV    -18.72mA   -15.2mA    -22.91mA
-700mV    -17.08mA   -13.69mA   -20.99mA
100mV     2.435mA    1.947mA    3.024mA
500mV     11.69mA    9.104mA    14.75mA
800mV     17.99mA    13.65mA    22.85mA
1.3V      27.3mA     19.15mA    35.06mA
1.6V      31.66mA    20.84mA    41.64mA
2V        35.7mA     21.69mA    48.47mA
2.4V      37.53mA    22.05mA    52.89mA
[GND Clamp]
|   Voltage   I(typ)   I(min)   I(max)
-1.2V     -16.71mA   -16.48mA   -17.08mA
-1.1V     -11.45mA   -11.17mA   -12mA
-1V       -7.044mA   -6.664mA   -7.704mA
-900mV    -3.726mA   -3.323mA   -4.269mA
-800mV    -1.68mA    -1.396mA   -2.168mA
-700mV    -639.3uA   -688.3uA   -837.8uA
-600mV    -234.1uA   -270.2uA   -259.4uA
-500mV    -75.38uA   -59.19uA   -89.09uA
-400mV    -14.89uA   -7.569uA   -8.332uA
2.4V      0A         0A         0A
[POWER Clamp]
|   Voltage   I(typ)   I(min)   I(max)
-1.2V     0A         0A         0A
0V        0A         0A         0A
2.4V      0A         0A         0A
[Ramp]
R_load = 50.00Ohm
|   typ   min   max
dV/dt_r   387.126mV/165.293ps 321.194mV/203.258ps 450.416mV/145.252ps
dV/dt_f   387.126mV/175.003ps 321.194mV/275.819ps 450.416mV/126.658ps
[Falling Waveform]
V_fixture = 1.200V
V_fixture_min = 1.140V
V_fixture_max = 1.260V
R_fixture = 50.00Ohm
|   Time   V(typ)   V(min)   V(max)
0s        1.2V       1.14V      1.26V
760ps     1.2V       1.14V      1.273V
970ps     1.204V     1.14V      642.1mV
1.09ns    1.195V     1.14V      561.5mV
1.21ns    927.4mV    1.14V      536.2mV
1.45ns    614.2mV    1.146V     518.5mV
1.64ns    580.2mV    1.115V     513.7mV
2ns       561.7mV    705.7mV    510.6mV
2.25ns    558mV      640.2mV    510mV
5ns       554.9mV    604.8mV    509.4mV
[Rising Waveform]
V_fixture = 1.200V
V_fixture_min = 1.140V
V_fixture_max = 1.260V
R_fixture = 50.00Ohm
|   Time   V(typ)   V(min)   V(max)
0s        554.9mV    604.8mV    509.4mV
590ps     552.7mV    604.9mV    535.9mV
650ps     545.6mV    604.9mV    632.6mV
730ps     554.9mV    605.5mV    954.4mV
790ps     578.6mV    604.8mV    1.091V
860ps     648.6mV    600.2mV    1.166V
1.04ns    1.07V      634.6mV    1.227V
1.31ns    1.175V     1.015V     1.248V
1.55ns    1.189V     1.112V     1.254V
5ns       1.2V       1.14V      1.26V
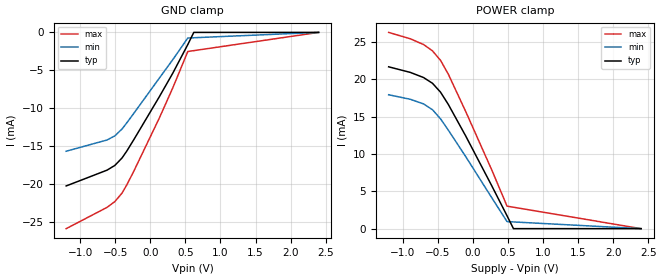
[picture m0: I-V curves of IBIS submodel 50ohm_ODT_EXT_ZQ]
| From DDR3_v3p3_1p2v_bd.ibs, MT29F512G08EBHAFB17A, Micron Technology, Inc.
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| SUBMODEL 50ohm_ODT_EXT_ZQ
[Submodel]   50ohm_ODT_EXT_ZQ
Submodel_type  Dynamic_clamp
[GND Clamp]
|   Voltage   I(typ)   I(min)   I(max)
-1.2V     -20.21mA   -15.64mA   -25.83mA
-617mV    -18.13mA   -14.16mA   -23.03mA
-506mV    -17.51mA   -13.62mA   -22.27mA
-403.5mV  -16.53mA   -12.71mA   -21.15mA
-334mV    -15.6mA    -11.89mA   -20.05mA
-233.5mV  -14.09mA   -10.63mA   -18.23mA
130mV     -8.449mA   -6.002mA   -11.24mA
322mV     -5.34mA    -3.568mA   -7.269mA
534.5mV   -1.602mA   -738.6uA   -2.516mA
620mV     0A         NA         NA
2.4V      0A         0A         0A
[POWER Clamp]
|   Voltage   I(typ)   I(min)   I(max)
-1.2V     21.67mA    17.93mA    26.28mA
-890mV    20.92mA    17.32mA    25.42mA
-701.5mV  20.23mA    16.7mA     24.65mA
-574.5mV  19.46mA    15.92mA    23.8mA
-460.5mV  18.28mA    14.71mA    22.54mA
-349mV    16.63mA    13.19mA    20.68mA
-99mV     12.37mA    9.616mA    15.64mA
271mV     5.727mA    4.131mA    7.845mA
488mV     1.725mA    946.3uA    3.015mA
580mV     0A         NA         NA
2.4V      0A         0A         0A
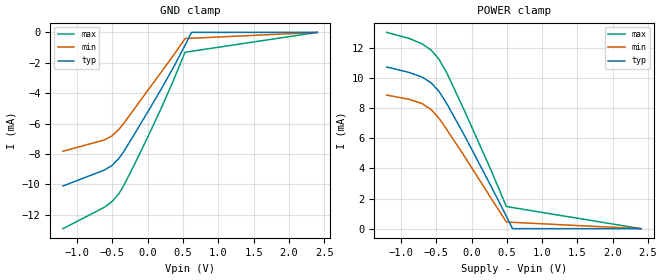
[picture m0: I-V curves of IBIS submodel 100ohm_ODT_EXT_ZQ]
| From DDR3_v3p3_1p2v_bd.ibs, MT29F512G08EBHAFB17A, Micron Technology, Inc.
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| SUBMODEL 100ohm_ODT_EXT_ZQ
[Submodel]   100ohm_ODT_EXT_ZQ
Submodel_type  Dynamic_clamp
[GND Clamp]
|   Voltage   I(typ)   I(min)   I(max)
-1.2V     -10.11mA   -7.821mA   -12.92mA
-617mV    -9.067mA   -7.085mA   -11.52mA
-505.5mV  -8.758mA   -6.811mA   -11.14mA
-403.5mV  -8.268mA   -6.358mA   -10.58mA
-334mV    -7.799mA   -5.949mA   -10.03mA
-190.5mV  -6.714mA   -5.038mA   -8.708mA
0V        -5.238mA   -3.821mA   -6.891mA
192.5mV   -3.716mA   -2.599mA   -4.974mA
355.5mV   -2.374mA   -1.561mA   -3.25mA
528mV     -844.3uA   -405.9uA   -1.307mA
619mV     0A         NA         NA
2.4V      0A         0A         0A
[POWER Clamp]
|   Voltage   I(typ)   I(min)   I(max)
-1.2V     10.74mA    8.877mA    13.04mA
-883mV    10.38mA    8.593mA    12.64mA
-699.5mV  10.07mA    8.307mA    12.28mA
-573mV    9.694mA    7.927mA    11.87mA
-460mV    9.119mA    7.33mA     11.26mA
-349mV    8.299mA    6.578mA    10.34mA
-99mV     6.185mA    4.8mA      7.83mA
273.5mV   2.85mA     2.05mA     3.916mA
493.5mV   825.8uA    440.9uA    1.469mA
581mV     0A         NA         NA
2.4V      0A         0A         0A
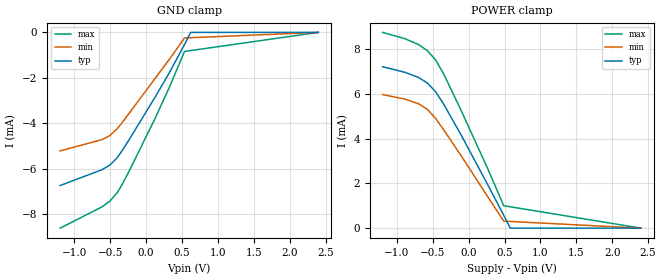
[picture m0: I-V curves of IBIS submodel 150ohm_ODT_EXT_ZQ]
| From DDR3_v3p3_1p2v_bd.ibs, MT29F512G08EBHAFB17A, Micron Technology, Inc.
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| SUBMODEL 150ohm_ODT_EXT_ZQ
[Submodel]   150ohm_ODT_EXT_ZQ
Submodel_type  Dynamic_clamp
[GND Clamp]
|   Voltage   I(typ)   I(min)   I(max)
-1.2V     -6.737mA   -5.212mA   -8.611mA
-616.5mV  -6.041mA   -4.719mA   -7.676mA
-505.5mV  -5.836mA   -4.538mA   -7.422mA
-403.5mV  -5.511mA   -4.237mA   -7.051mA
-334mV    -5.199mA   -3.965mA   -6.684mA
-234mV    -4.7mA     -3.544mA   -6.079mA
130mV     -2.817mA   -2.001mA   -3.748mA
322mV     -1.78mA    -1.189mA   -2.423mA
534.5mV   -533.7uA   -246.1uA   -838.3uA
620mV     0A         NA         NA
2.4V      0A         0A         0A
[POWER Clamp]
|   Voltage   I(typ)   I(min)   I(max)
-1.2V     7.214mA    5.969mA    8.749mA
-889mV    6.964mA    5.767mA    8.466mA
-700.5mV  6.737mA    5.561mA    8.208mA
-573.5mV  6.48mA     5.302mA    7.926mA
-459.5mV  6.089mA    4.898mA    7.509mA
-348.5mV  5.54mA     4.394mA    6.891mA
-99mV     4.125mA    3.206mA    5.215mA
271.5mV   1.906mA    1.375mA    2.612mA
488.5mV   572.2uA    313.2uA    1.002mA
580mV     0A         NA         NA
2.4V      0A         0A         0A
